# Generated by FakeRAM 2.0
VERSION 5.7 ;
BUSBITCHARS "[]" ;
PROPERTYDEFINITIONS
  MACRO width INTEGER ;
  MACRO depth INTEGER ;
  MACRO banks INTEGER ;
END PROPERTYDEFINITIONS
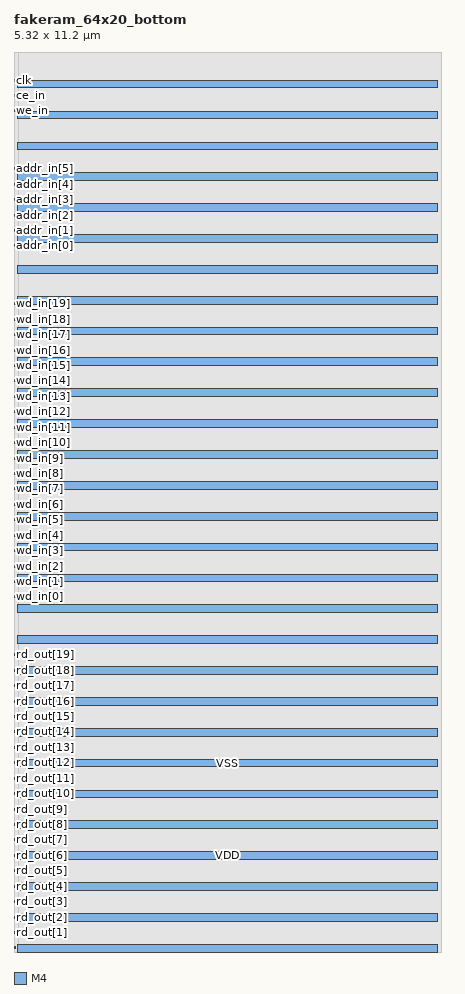
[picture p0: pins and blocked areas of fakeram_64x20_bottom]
MACRO fakeram_64x20_bottom
  PROPERTY width 20 ;
  PROPERTY depth 64 ;
  PROPERTY banks 2 ;
  FOREIGN fakeram_64x20_bottom 0 0 ;
  SYMMETRY X Y R90 ;
  SIZE 5.320 BY 11.200 ;
  CLASS BLOCK ;
  PIN rd_out[0]
    DIRECTION OUTPUT ;
    USE SIGNAL ;
    SHAPE ABUTMENT ;
    PORT
      LAYER M4 ;
      RECT 0.000 0.039 0.024 0.063 ;
    END
  END rd_out[0]
  PIN rd_out[1]
    DIRECTION OUTPUT ;
    USE SIGNAL ;
    SHAPE ABUTMENT ;
    PORT
      LAYER M4 ;
      RECT 0.000 0.231 0.024 0.255 ;
    END
  END rd_out[1]
  PIN rd_out[2]
    DIRECTION OUTPUT ;
    USE SIGNAL ;
    SHAPE ABUTMENT ;
    PORT
      LAYER M4 ;
      RECT 0.000 0.423 0.024 0.447 ;
    END
  END rd_out[2]
  PIN rd_out[3]
    DIRECTION OUTPUT ;
    USE SIGNAL ;
    SHAPE ABUTMENT ;
    PORT
      LAYER M4 ;
      RECT 0.000 0.615 0.024 0.639 ;
    END
  END rd_out[3]
  PIN rd_out[4]
    DIRECTION OUTPUT ;
    USE SIGNAL ;
    SHAPE ABUTMENT ;
    PORT
      LAYER M4 ;
      RECT 0.000 0.807 0.024 0.831 ;
    END
  END rd_out[4]
  PIN rd_out[5]
    DIRECTION OUTPUT ;
    USE SIGNAL ;
    SHAPE ABUTMENT ;
    PORT
      LAYER M4 ;
      RECT 0.000 0.999 0.024 1.023 ;
    END
  END rd_out[5]
  PIN rd_out[6]
    DIRECTION OUTPUT ;
    USE SIGNAL ;
    SHAPE ABUTMENT ;
    PORT
      LAYER M4 ;
      RECT 0.000 1.191 0.024 1.215 ;
    END
  END rd_out[6]
  PIN rd_out[7]
    DIRECTION OUTPUT ;
    USE SIGNAL ;
    SHAPE ABUTMENT ;
    PORT
      LAYER M4 ;
      RECT 0.000 1.383 0.024 1.407 ;
    END
  END rd_out[7]
  PIN rd_out[8]
    DIRECTION OUTPUT ;
    USE SIGNAL ;
    SHAPE ABUTMENT ;
    PORT
      LAYER M4 ;
      RECT 0.000 1.575 0.024 1.599 ;
    END
  END rd_out[8]
  PIN rd_out[9]
    DIRECTION OUTPUT ;
    USE SIGNAL ;
    SHAPE ABUTMENT ;
    PORT
      LAYER M4 ;
      RECT 0.000 1.767 0.024 1.791 ;
    END
  END rd_out[9]
  PIN rd_out[10]
    DIRECTION OUTPUT ;
    USE SIGNAL ;
    SHAPE ABUTMENT ;
    PORT
      LAYER M4 ;
      RECT 0.000 1.959 0.024 1.983 ;
    END
  END rd_out[10]
  PIN rd_out[11]
    DIRECTION OUTPUT ;
    USE SIGNAL ;
    SHAPE ABUTMENT ;
    PORT
      LAYER M4 ;
      RECT 0.000 2.151 0.024 2.175 ;
    END
  END rd_out[11]
  PIN rd_out[12]
    DIRECTION OUTPUT ;
    USE SIGNAL ;
    SHAPE ABUTMENT ;
    PORT
      LAYER M4 ;
      RECT 0.000 2.343 0.024 2.367 ;
    END
  END rd_out[12]
  PIN rd_out[13]
    DIRECTION OUTPUT ;
    USE SIGNAL ;
    SHAPE ABUTMENT ;
    PORT
      LAYER M4 ;
      RECT 0.000 2.535 0.024 2.559 ;
    END
  END rd_out[13]
  PIN rd_out[14]
    DIRECTION OUTPUT ;
    USE SIGNAL ;
    SHAPE ABUTMENT ;
    PORT
      LAYER M4 ;
      RECT 0.000 2.727 0.024 2.751 ;
    END
  END rd_out[14]
  PIN rd_out[15]
    DIRECTION OUTPUT ;
    USE SIGNAL ;
    SHAPE ABUTMENT ;
    PORT
      LAYER M4 ;
      RECT 0.000 2.919 0.024 2.943 ;
    END
  END rd_out[15]
  PIN rd_out[16]
    DIRECTION OUTPUT ;
    USE SIGNAL ;
    SHAPE ABUTMENT ;
    PORT
      LAYER M4 ;
      RECT 0.000 3.111 0.024 3.135 ;
    END
  END rd_out[16]
  PIN rd_out[17]
    DIRECTION OUTPUT ;
    USE SIGNAL ;
    SHAPE ABUTMENT ;
    PORT
      LAYER M4 ;
      RECT 0.000 3.303 0.024 3.327 ;
    END
  END rd_out[17]
  PIN rd_out[18]
    DIRECTION OUTPUT ;
    USE SIGNAL ;
    SHAPE ABUTMENT ;
    PORT
      LAYER M4 ;
      RECT 0.000 3.495 0.024 3.519 ;
    END
  END rd_out[18]
  PIN rd_out[19]
    DIRECTION OUTPUT ;
    USE SIGNAL ;
    SHAPE ABUTMENT ;
    PORT
      LAYER M4 ;
      RECT 0.000 3.687 0.024 3.711 ;
    END
  END rd_out[19]
  PIN wd_in[0]
    DIRECTION INPUT ;
    USE SIGNAL ;
    SHAPE ABUTMENT ;
    PORT
      LAYER M4 ;
      RECT 0.000 4.407 0.024 4.431 ;
    END
  END wd_in[0]
  PIN wd_in[1]
    DIRECTION INPUT ;
    USE SIGNAL ;
    SHAPE ABUTMENT ;
    PORT
      LAYER M4 ;
      RECT 0.000 4.599 0.024 4.623 ;
    END
  END wd_in[1]
  PIN wd_in[2]
    DIRECTION INPUT ;
    USE SIGNAL ;
    SHAPE ABUTMENT ;
    PORT
      LAYER M4 ;
      RECT 0.000 4.791 0.024 4.815 ;
    END
  END wd_in[2]
  PIN wd_in[3]
    DIRECTION INPUT ;
    USE SIGNAL ;
    SHAPE ABUTMENT ;
    PORT
      LAYER M4 ;
      RECT 0.000 4.983 0.024 5.007 ;
    END
  END wd_in[3]
  PIN wd_in[4]
    DIRECTION INPUT ;
    USE SIGNAL ;
    SHAPE ABUTMENT ;
    PORT
      LAYER M4 ;
      RECT 0.000 5.175 0.024 5.199 ;
    END
  END wd_in[4]
  PIN wd_in[5]
    DIRECTION INPUT ;
    USE SIGNAL ;
    SHAPE ABUTMENT ;
    PORT
      LAYER M4 ;
      RECT 0.000 5.367 0.024 5.391 ;
    END
  END wd_in[5]
  PIN wd_in[6]
    DIRECTION INPUT ;
    USE SIGNAL ;
    SHAPE ABUTMENT ;
    PORT
      LAYER M4 ;
      RECT 0.000 5.559 0.024 5.583 ;
    END
  END wd_in[6]
  PIN wd_in[7]
    DIRECTION INPUT ;
    USE SIGNAL ;
    SHAPE ABUTMENT ;
    PORT
      LAYER M4 ;
      RECT 0.000 5.751 0.024 5.775 ;
    END
  END wd_in[7]
  PIN wd_in[8]
    DIRECTION INPUT ;
    USE SIGNAL ;
    SHAPE ABUTMENT ;
    PORT
      LAYER M4 ;
      RECT 0.000 5.943 0.024 5.967 ;
    END
  END wd_in[8]
  PIN wd_in[9]
    DIRECTION INPUT ;
    USE SIGNAL ;
    SHAPE ABUTMENT ;
    PORT
      LAYER M4 ;
      RECT 0.000 6.135 0.024 6.159 ;
    END
  END wd_in[9]
  PIN wd_in[10]
    DIRECTION INPUT ;
    USE SIGNAL ;
    SHAPE ABUTMENT ;
    PORT
      LAYER M4 ;
      RECT 0.000 6.327 0.024 6.351 ;
    END
  END wd_in[10]
  PIN wd_in[11]
    DIRECTION INPUT ;
    USE SIGNAL ;
    SHAPE ABUTMENT ;
    PORT
      LAYER M4 ;
      RECT 0.000 6.519 0.024 6.543 ;
    END
  END wd_in[11]
  PIN wd_in[12]
    DIRECTION INPUT ;
    USE SIGNAL ;
    SHAPE ABUTMENT ;
    PORT
      LAYER M4 ;
      RECT 0.000 6.711 0.024 6.735 ;
    END
  END wd_in[12]
  PIN wd_in[13]
    DIRECTION INPUT ;
    USE SIGNAL ;
    SHAPE ABUTMENT ;
    PORT
      LAYER M4 ;
      RECT 0.000 6.903 0.024 6.927 ;
    END
  END wd_in[13]
  PIN wd_in[14]
    DIRECTION INPUT ;
    USE SIGNAL ;
    SHAPE ABUTMENT ;
    PORT
      LAYER M4 ;
      RECT 0.000 7.095 0.024 7.119 ;
    END
  END wd_in[14]
  PIN wd_in[15]
    DIRECTION INPUT ;
    USE SIGNAL ;
    SHAPE ABUTMENT ;
    PORT
      LAYER M4 ;
      RECT 0.000 7.287 0.024 7.311 ;
    END
  END wd_in[15]
  PIN wd_in[16]
    DIRECTION INPUT ;
    USE SIGNAL ;
    SHAPE ABUTMENT ;
    PORT
      LAYER M4 ;
      RECT 0.000 7.479 0.024 7.503 ;
    END
  END wd_in[16]
  PIN wd_in[17]
    DIRECTION INPUT ;
    USE SIGNAL ;
    SHAPE ABUTMENT ;
    PORT
      LAYER M4 ;
      RECT 0.000 7.671 0.024 7.695 ;
    END
  END wd_in[17]
  PIN wd_in[18]
    DIRECTION INPUT ;
    USE SIGNAL ;
    SHAPE ABUTMENT ;
    PORT
      LAYER M4 ;
      RECT 0.000 7.863 0.024 7.887 ;
    END
  END wd_in[18]
  PIN wd_in[19]
    DIRECTION INPUT ;
    USE SIGNAL ;
    SHAPE ABUTMENT ;
    PORT
      LAYER M4 ;
      RECT 0.000 8.055 0.024 8.079 ;
    END
  END wd_in[19]
  PIN addr_in[0]
    DIRECTION INPUT ;
    USE SIGNAL ;
    SHAPE ABUTMENT ;
    PORT
      LAYER M4 ;
      RECT 0.000 8.775 0.024 8.799 ;
    END
  END addr_in[0]
  PIN addr_in[1]
    DIRECTION INPUT ;
    USE SIGNAL ;
    SHAPE ABUTMENT ;
    PORT
      LAYER M4 ;
      RECT 0.000 8.967 0.024 8.991 ;
    END
  END addr_in[1]
  PIN addr_in[2]
    DIRECTION INPUT ;
    USE SIGNAL ;
    SHAPE ABUTMENT ;
    PORT
      LAYER M4 ;
      RECT 0.000 9.159 0.024 9.183 ;
    END
  END addr_in[2]
  PIN addr_in[3]
    DIRECTION INPUT ;
    USE SIGNAL ;
    SHAPE ABUTMENT ;
    PORT
      LAYER M4 ;
      RECT 0.000 9.351 0.024 9.375 ;
    END
  END addr_in[3]
  PIN addr_in[4]
    DIRECTION INPUT ;
    USE SIGNAL ;
    SHAPE ABUTMENT ;
    PORT
      LAYER M4 ;
      RECT 0.000 9.543 0.024 9.567 ;
    END
  END addr_in[4]
  PIN addr_in[5]
    DIRECTION INPUT ;
    USE SIGNAL ;
    SHAPE ABUTMENT ;
    PORT
      LAYER M4 ;
      RECT 0.000 9.735 0.024 9.759 ;
    END
  END addr_in[5]
  PIN we_in
    DIRECTION INPUT ;
    USE SIGNAL ;
    SHAPE ABUTMENT ;
    PORT
      LAYER M4 ;
      RECT 0.000 10.455 0.024 10.479 ;
    END
  END we_in
  PIN ce_in
    DIRECTION INPUT ;
    USE SIGNAL ;
    SHAPE ABUTMENT ;
    PORT
      LAYER M4 ;
      RECT 0.000 10.647 0.024 10.671 ;
    END
  END ce_in
  PIN clk
    DIRECTION INPUT ;
    USE SIGNAL ;
    SHAPE ABUTMENT ;
    PORT
      LAYER M4 ;
      RECT 0.000 10.839 0.024 10.863 ;
    END
  END clk
  PIN VSS
    DIRECTION INOUT ;
    USE GROUND ;
    PORT
      LAYER M4 ;
      RECT 0.048 0.000 5.272 0.096 ;
      RECT 0.048 0.768 5.272 0.864 ;
      RECT 0.048 1.536 5.272 1.632 ;
      RECT 0.048 2.304 5.272 2.400 ;
      RECT 0.048 3.072 5.272 3.168 ;
      RECT 0.048 3.840 5.272 3.936 ;
      RECT 0.048 4.608 5.272 4.704 ;
      RECT 0.048 5.376 5.272 5.472 ;
      RECT 0.048 6.144 5.272 6.240 ;
      RECT 0.048 6.912 5.272 7.008 ;
      RECT 0.048 7.680 5.272 7.776 ;
      RECT 0.048 8.448 5.272 8.544 ;
      RECT 0.048 9.216 5.272 9.312 ;
      RECT 0.048 9.984 5.272 10.080 ;
      RECT 0.048 10.752 5.272 10.848 ;
    END
  END VSS
  PIN VDD
    DIRECTION INOUT ;
    USE POWER ;
    PORT
      LAYER M4 ;
      RECT 0.048 0.384 5.272 0.480 ;
      RECT 0.048 1.152 5.272 1.248 ;
      RECT 0.048 1.920 5.272 2.016 ;
      RECT 0.048 2.688 5.272 2.784 ;
      RECT 0.048 3.456 5.272 3.552 ;
      RECT 0.048 4.224 5.272 4.320 ;
      RECT 0.048 4.992 5.272 5.088 ;
      RECT 0.048 5.760 5.272 5.856 ;
      RECT 0.048 6.528 5.272 6.624 ;
      RECT 0.048 7.296 5.272 7.392 ;
      RECT 0.048 8.064 5.272 8.160 ;
      RECT 0.048 8.832 5.272 8.928 ;
      RECT 0.048 9.600 5.272 9.696 ;
      RECT 0.048 10.368 5.272 10.464 ;
    END
  END VDD
  OBS
    LAYER M1 ;
    RECT 0 0 5.320 11.200 ;
    LAYER M2 ;
    RECT 0 0 5.320 11.200 ;
    LAYER M3 ;
    RECT 0.059 0.000 5.320 11.200 ;
    LAYER M4 ;
    RECT 0.059 0.000 5.320 11.200 ;
  END
END fakeram_64x20_bottom

END LIBRARY
